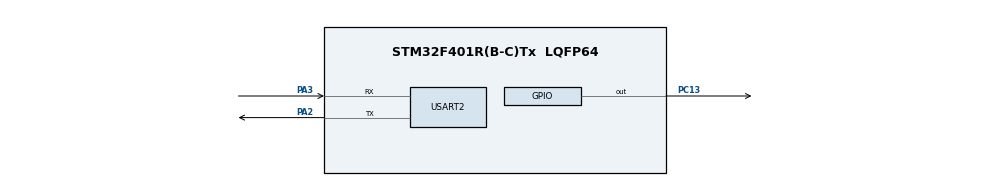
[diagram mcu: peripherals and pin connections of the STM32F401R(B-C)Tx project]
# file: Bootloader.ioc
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Mcu.Family=STM32F4
Mcu.Name=STM32F401R(B-C)Tx
Mcu.Package=LQFP64
NVIC.PriorityGroup=NVIC_PRIORITYGROUP_4
PA2.Mode=Asynchronous
PA2.Signal=USART2_TX
PA3.Mode=Asynchronous
PA3.Signal=USART2_RX
PC13-ANTI_TAMP.Signal=GPIO_Output
ProjectManager.HeapSize=0x200
ProjectManager.StackSize=0x400
ProjectManager.TargetToolchain=STM32CubeIDE
RCC.48MHZClocksFreq_Value=42000000
RCC.AHBFreq_Value=84000000
RCC.APB1CLKDivider=RCC_HCLK_DIV2
RCC.APB1Freq_Value=42000000
RCC.APB1TimFreq_Value=84000000
RCC.APB2Freq_Value=84000000
RCC.APB2TimFreq_Value=84000000
RCC.CortexFreq_Value=84000000
RCC.HCLKFreq_Value=84000000
RCC.HSE_VALUE=16000000
RCC.HSI_VALUE=16000000
RCC.LSE_VALUE=32768
RCC.PLLM=8
RCC.PLLN=84
RCC.SYSCLKFreq_VALUE=84000000
RCC.SYSCLKSource=RCC_SYSCLKSOURCE_PLLCLK
RCC.VCOOutputFreq_Value=168000000
USART2.VirtualMode=VM_ASYNC
VP_CRC_VS_CRC.Mode=CRC_Activate
board=custom

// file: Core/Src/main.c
/* USER CODE BEGIN Header */
/**
  ******************************************************************************
  * @file           : main.c
  * @brief          : Main program body
  ******************************************************************************
  * @attention
  *
  * Copyright (c) 2024 STMicroelectronics.
  * All rights reserved.
  *
  * This software is licensed under terms that can be found in the LICENSE file
  * in the root directory of this software component.
  * If no LICENSE file comes with this software, it is provided AS-IS.
  *
  ******************************************************************************
  */
/* USER CODE END Header */
#include "main.h"

/* USER CODE BEGIN Includes */
#include "helperFunctions/helperFunctions.h"
/* USER CODE END Includes */

CRC_HandleTypeDef hcrc;

UART_HandleTypeDef huart2;

void SystemClock_Config(void);
static void MX_GPIO_Init(void);
static void MX_USART2_UART_Init(void);
static void MX_CRC_Init(void);

int main(void)
{

  /* MCU Configuration--------------------------------------------------------*/

  /* Reset of all peripherals, Initializes the Flash interface and the Systick. */
  HAL_Init();

  /* Configure the system clock */
  SystemClock_Config();

  /* Initialize all configured peripherals */
  MX_GPIO_Init();
  MX_USART2_UART_Init();
  MX_CRC_Init();
  /* USER CODE BEGIN 2 */
  HAL_GPIO_WritePin(GPIOC, GPIO_PIN_13, GPIO_PIN_SET);

  /* USER CODE END 2 */

  /* Infinite loop */
  while (1)
  {

    /* USER CODE BEGIN 3 */
	  turnLedOn();
	  Bootloader_Fetch_Host_Command();
	  turnLedOff();
	  HAL_Delay(500);

  }
  /* USER CODE END 3 */
}

void SystemClock_Config(void)
{
  RCC_OscInitTypeDef RCC_OscInitStruct = {0};
  RCC_ClkInitTypeDef RCC_ClkInitStruct = {0};

  /** Configure the main internal regulator output voltage
  */
  __HAL_RCC_PWR_CLK_ENABLE();
  __HAL_PWR_VOLTAGESCALING_CONFIG(PWR_REGULATOR_VOLTAGE_SCALE2);

  /** Initializes the RCC Oscillators according to the specified parameters
  * in the RCC_OscInitTypeDef structure.
  */
  RCC_OscInitStruct.OscillatorType = RCC_OSCILLATORTYPE_HSI;
  RCC_OscInitStruct.HSIState = RCC_HSI_ON;
  RCC_OscInitStruct.HSICalibrationValue = RCC_HSICALIBRATION_DEFAULT;
  RCC_OscInitStruct.PLL.PLLState = RCC_PLL_NONE;
  if (HAL_RCC_OscConfig(&RCC_OscInitStruct) != HAL_OK)
  {
    Error_Handler();
  }

  /** Initializes the CPU, AHB and APB buses clocks
  */
  RCC_ClkInitStruct.ClockType = RCC_CLOCKTYPE_HCLK|RCC_CLOCKTYPE_SYSCLK
                              |RCC_CLOCKTYPE_PCLK1|RCC_CLOCKTYPE_PCLK2;
  RCC_ClkInitStruct.SYSCLKSource = RCC_SYSCLKSOURCE_HSI;
  RCC_ClkInitStruct.AHBCLKDivider = RCC_SYSCLK_DIV1;
  RCC_ClkInitStruct.APB1CLKDivider = RCC_HCLK_DIV2;
  RCC_ClkInitStruct.APB2CLKDivider = RCC_HCLK_DIV1;

  if (HAL_RCC_ClockConfig(&RCC_ClkInitStruct, FLASH_LATENCY_0) != HAL_OK)
  {
    Error_Handler();
  }
}

static void MX_CRC_Init(void)
{

  hcrc.Instance = CRC;
  if (HAL_CRC_Init(&hcrc) != HAL_OK)
  {
    Error_Handler();
  }

}

static void MX_USART2_UART_Init(void)
{

  huart2.Instance = USART2;
  huart2.Init.BaudRate = 115200;
  huart2.Init.WordLength = UART_WORDLENGTH_8B;
  huart2.Init.StopBits = UART_STOPBITS_1;
  huart2.Init.Parity = UART_PARITY_NONE;
  huart2.Init.Mode = UART_MODE_TX_RX;
  huart2.Init.HwFlowCtl = UART_HWCONTROL_NONE;
  huart2.Init.OverSampling = UART_OVERSAMPLING_16;
  if (HAL_UART_Init(&huart2) != HAL_OK)
  {
    Error_Handler();
  }

}

static void MX_GPIO_Init(void)
{
  GPIO_InitTypeDef GPIO_InitStruct = {0};

  /* GPIO Ports Clock Enable */
  __HAL_RCC_GPIOC_CLK_ENABLE();
  __HAL_RCC_GPIOH_CLK_ENABLE();
  __HAL_RCC_GPIOA_CLK_ENABLE();

  /*Configure GPIO pin Output Level */
  HAL_GPIO_WritePin(GPIOC, GPIO_PIN_13, GPIO_PIN_RESET);

  /*Configure GPIO pin : PC13 */
  GPIO_InitStruct.Pin = GPIO_PIN_13;
  GPIO_InitStruct.Mode = GPIO_MODE_OUTPUT_PP;
  GPIO_InitStruct.Pull = GPIO_NOPULL;
  GPIO_InitStruct.Speed = GPIO_SPEED_FREQ_LOW;
  HAL_GPIO_Init(GPIOC, &GPIO_InitStruct);

}

void Error_Handler(void)
{
  __disable_irq();
  while (1)
  {
  }
}
